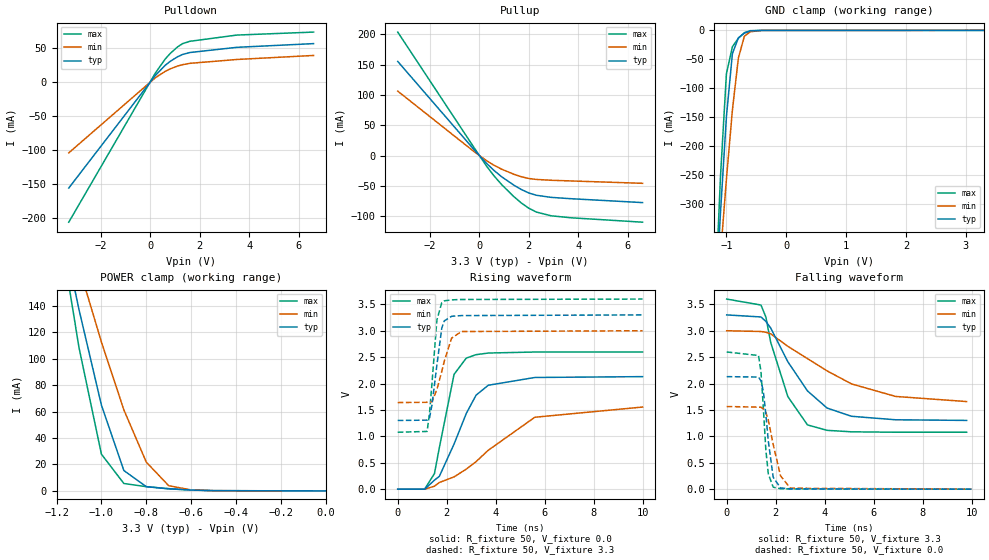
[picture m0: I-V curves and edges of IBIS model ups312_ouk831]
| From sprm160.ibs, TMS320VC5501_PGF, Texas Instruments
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[Model]   ups312_ouk831
Model_type   I/O
Vinh = 2.00
Vinl = 0.80
Enable   Active-Low
Polarity   Non-Inverting
| signals   A, GZ, Y
Vmeas = 1.5
|   typ   min   max
C_comp   2.553p   2.541p   2.555p
|   typ   min   max
[Temperature Range]   25   -40   125
|   typ   min   max
[Voltage Range]   3.30V   3.00V   3.60V
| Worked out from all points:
|   slope of the pulldown table from 0 to 0.495 V, typ, clamps not added: 24 ohm
|   slope of the pullup table from 0 to 0.495 V, typ, clamps not added: 23.8 ohm
|   GND clamp passes 1 mA (typ) near -0.60 V on its own axis
|   POWER clamp passes 1 mA (typ) near -0.64 V on its own axis
|   rising waveform, R_fixture 50, V_fixture 0.0: 20-80 % time 1.23ns typ, 2.49ns min, 656ps max; typ from 0 V to 2.13 V
|   falling waveform, R_fixture 50, V_fixture 3.3: 20-80 % time 1.7ns typ, 3.01ns min, 1ns max; typ from 3.3 V to 1.3 V
|   rising waveform, R_fixture 50, V_fixture 3.3: 20-80 % time 320ps typ, 467ps min, 255ps max; typ from 1.3 V to 3.3 V
|   falling waveform, R_fixture 50, V_fixture 0.0: 20-80 % time 289ps typ, 431ps min, 228ps max; typ from 2.13 V to 0 V
[Pulldown]
|   Voltage   I(typ)   I(min)   I(max)
-3.3V     -155.6mA   -104.1mA   -205.6mA
200mV     9.243mA    5.866mA    12.7mA
600mV     24.13mA    15.28mA    33.3mA
800mV     29.87mA    18.87mA    41.37mA
1.1V      36.63mA    23.02mA    51.08mA
1.3V      39.97mA    25.04mA    55.82mA
1.6V      42.83mA    27mA       59.29mA
3.5V      50.44mA    32.65mA    68.4mA
6.6V      55.87mA    38.54mA    72.75mA
[GND_clamp]
|   Voltage   I(typ)   I(min)   I(max)
-3.3V     -4.923A    -3.708A    -6.396A
-1.2V     -505mA     -529.2mA   -496.8mA
-1.1V     -317.1mA   -390.1mA   -254.5mA
-1V       -149.5mA   -257.6mA   -75.13mA
-900mV    -40.22mA   -138mA     -28.39mA
-800mV    -13.05mA   -47.86mA   -13.64mA
-700mV    -4.763mA   -10.19mA   -4.082mA
-600mV    -990.2uA   -2.384mA   -580.2uA
-400mV    -63.28uA   -85.04uA   -88.36uA
3.3V      355.3pA    30.66uA    -59.86uA
[Pullup]
|   Voltage   I(typ)   I(min)   I(max)
-3.3V     155.5mA    106.5mA    203.9mA
-200mV    9.306mA    6.233mA    12.42mA
300mV     -13.07mA   -8.546mA   -17.75mA
600mV     -24.68mA   -16mA      -33.65mA
900mV     -34.78mA   -22.33mA   -47.64mA
1.4V      -48.81mA   -30.78mA   -67.77mA
1.7V      -55.9mA    -34.78mA   -78.19mA
2V        -61.53mA   -37.68mA   -86.71mA
2.3V      -65.31mA   -39.22mA   -93.01mA
2.9V      -68.83mA   -40.61mA   -99.22mA
3.7V      -71.03mA   -41.73mA   -102.5mA
6.6V      -77.46mA   -45.65mA   -109.8mA
[POWER_clamp]
|   Voltage   I(typ)   I(min)   I(max)
-3.3V     2.112A     1.594A     2.742A
-1.2V     218.2mA    229.3mA    213.3mA
-1.1V     137.3mA    169.6mA    108.6mA
-1V       64.95mA    112.7mA    27.82mA
-900mV    15.44mA    61.33mA    5.616mA
-800mV    3.218mA    21.79mA    3.224mA
-700mV    1.543mA    3.926mA    1.724mA
-600mV    687.2uA    776.7uA    678uA
-500mV    216.3uA    199.4uA    185.5uA
0V        1pA        1pA        1pA
[Ramp]
|   I(typ)   I(min)   I(max)
dV/dt_r   1.278/1.222n   0.933/2.492n   1.559/0.651n
dV/dt_f   1.199/1.697n   0.806/3.013n   1.513/1.002n
[Rising Waveform]
R_fixture = 50
V_fixture = 0.0
|  pu_on
|  TIME   V(typ)   V(min)   V(max)
0s        6nV        19nV       5nV
1.1ns     -38.99uV   -123.7uV   2.338mV
1.5ns     170.2mV    55.66mV    294.4mV
1.7ns     242.6mV    126mV      786.2mV
2.3ns     853.4mV    232.3mV    2.173V
2.8ns     1.434V     379mV      2.482V
3.2ns     1.78V      521.6mV    2.547V
3.7ns     1.968V     737.5mV    2.578V
5.6ns     2.115V     1.362V     2.597V
10ns      2.131V     1.555V     2.598V
[Falling Waveform]
R_fixture = 50
V_fixture = 3.3
V_fixture_min = 3.0
V_fixture_max = 3.6
|  pd_on
|  TIME   V(typ)   V(min)   V(max)
0s        3.3V       3V         3.6V
1.4ns     3.261V     2.986V     3.487V
1.6ns     3.178V     2.972V     3.26V
1.8ns     3.05V      2.941V     2.776V
2.5ns     2.411V     2.705V     1.751V
3.3ns     1.861V     2.472V     1.217V
4.1ns     1.536V     2.24V      1.114V
5.1ns     1.38V      1.993V     1.086V
6.9ns     1.314V     1.756V     1.078V
9.8ns     1.302V     1.659V     1.078V
[Rising Waveform]
R_fixture = 50
V_fixture = 3.3
V_fixture_min = 3.0
V_fixture_max = 3.6
|  pd_off
|  TIME   V(typ)   V(min)   V(max)
0s        1.301V     1.64V      1.078V
1.2ns     1.307V     1.645V     1.093V
1.3ns     1.351V     1.649V     1.446V
1.4ns     1.6V       1.655V     2.01V
1.6ns     2.352V     1.888V     3.205V
1.8ns     3.051V     2.233V     3.532V
1.9ns     3.186V     2.421V     3.566V
2.2ns     3.274V     2.86V      3.585V
2.6ns     3.287V     2.985V     3.592V
10ns      3.3V       3V         3.6V
[Falling Waveform]
R_fixture = 50
V_fixture = 0.0
|  pu_off
|  TIME   V(typ)   V(min)   V(max)
0s        2.131V     1.565V     2.598V
1.3ns     2.123V     1.554V     2.531V
1.4ns     2.052V     1.55V      2.229V
1.5ns     1.846V     1.525V     1.517V
1.6ns     1.417V     1.453V     740.9mV
1.7ns     912.3mV    1.311V     288.5mV
1.9ns     223.6mV    846.1mV    38.11mV
2.2ns     23mV       251.7mV    7.072mV
2.6ns     5.593mV    18.04mV    3.563mV
10ns      12.77uV    69uV       400nV
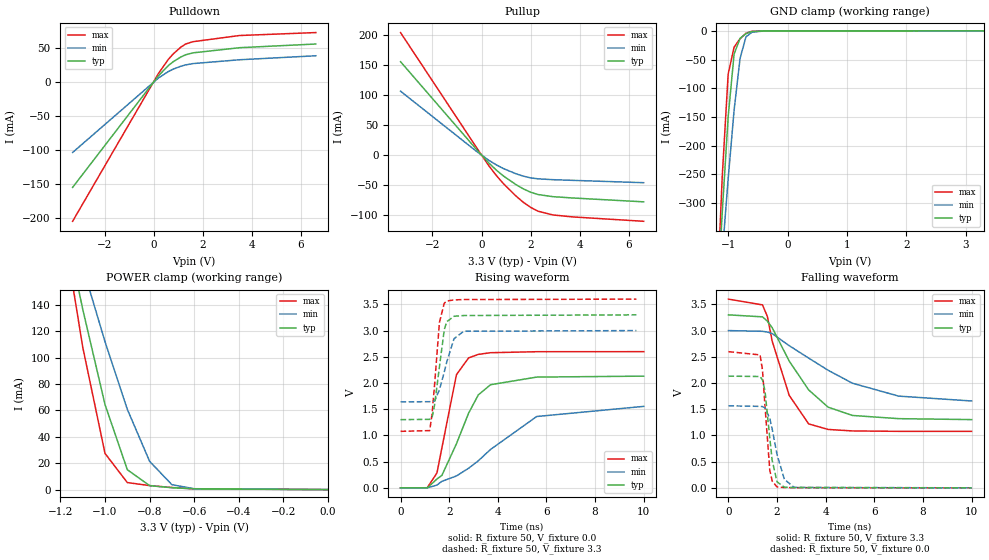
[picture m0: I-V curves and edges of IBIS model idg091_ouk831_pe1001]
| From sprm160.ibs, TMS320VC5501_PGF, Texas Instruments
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[Model]   idg091_ouk831_pe1001
| I/O with pulldown
Model_type   I/O
Vinh = 2.00
Vinl = 0.80
Enable   Active-Low
Polarity   Non-Inverting
| signals   A, GZ, Y
Vmeas = 1.5
|   typ   min   max
C_comp   1.997p   1.996p   1.999p
|   typ   min   max
[Temperature Range]   25   -40   125
|   typ   min   max
[Voltage Range]   3.30V   3.00V   3.60V
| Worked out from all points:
|   slope of the pulldown table from 0 to 0.495 V, typ, clamps not added: 24 ohm
|   slope of the pullup table from 0 to 0.495 V, typ, clamps not added: 23.8 ohm
|   GND clamp passes 1 mA (typ) near -0.60 V on its own axis
|   POWER clamp passes 1 mA (typ) near -0.65 V on its own axis
|   rising waveform, R_fixture 50, V_fixture 0.0: 20-80 % time 1.22ns typ, 2.48ns min, 657ps max; typ from 0 V to 2.13 V
|   falling waveform, R_fixture 50, V_fixture 3.3: 20-80 % time 1.7ns typ, 3.02ns min, 1.01ns max; typ from 3.3 V to 1.3 V
|   rising waveform, R_fixture 50, V_fixture 3.3: 20-80 % time 323ps typ, 470ps min, 259ps max; typ from 1.3 V to 3.3 V
|   falling waveform, R_fixture 50, V_fixture 0.0: 20-80 % time 296ps typ, 438ps min, 236ps max; typ from 2.13 V to 0 V
[Pulldown]
|   Voltage   I(typ)   I(min)   I(max)
-3.3V     -155.6mA   -104.1mA   -205.6mA
200mV     9.243mA    5.866mA    12.7mA
600mV     24.13mA    15.28mA    33.3mA
800mV     29.87mA    18.87mA    41.37mA
1.1V      36.63mA    23.02mA    51.08mA
1.3V      39.97mA    25.04mA    55.82mA
1.6V      42.83mA    27mA       59.29mA
3.5V      50.44mA    32.65mA    68.4mA
6.6V      55.87mA    38.54mA    72.75mA
[GND_clamp]
|   Voltage   I(typ)   I(min)   I(max)
-3.3V     -4.926A    -3.71A     -6.4A
-1.2V     -505.4mA   -529.6mA   -497.2mA
-1.1V     -317.4mA   -390.5mA   -254.7mA
-1V       -149.7mA   -257.9mA   -75.19mA
-900mV    -40.29mA   -138.2mA   -28.38mA
-800mV    -13.05mA   -47.97mA   -13.59mA
-700mV    -4.731mA   -10.23mA   -4.028mA
-600mV    -956.5uA   -2.389mA   -531.5uA
-400mV    -40.57uA   -71.55uA   -55.69uA
3.3V      100.3uA    53.84uA    176.6uA
[Pullup]
|   Voltage   I(typ)   I(min)   I(max)
-3.3V     155.5mA    106.5mA    203.9mA
-200mV    9.306mA    6.233mA    12.42mA
300mV     -13.07mA   -8.546mA   -17.75mA
600mV     -24.68mA   -16mA      -33.65mA
900mV     -34.78mA   -22.33mA   -47.64mA
1.4V      -48.81mA   -30.78mA   -67.77mA
1.7V      -55.9mA    -34.78mA   -78.19mA
2V        -61.53mA   -37.68mA   -86.71mA
2.3V      -65.31mA   -39.22mA   -93.01mA
2.9V      -68.83mA   -40.61mA   -99.22mA
3.7V      -71.03mA   -41.73mA   -102.5mA
6.6V      -77.46mA   -45.65mA   -109.8mA
[POWER_clamp]
|   Voltage   I(typ)   I(min)   I(max)
-3.3V     2.105A     1.588A     2.734A
-1.2V     217.1mA    228.2mA    212.4mA
-1.1V     136.6mA    168.7mA    107.9mA
-1V       64.4mA     112mA      27.37mA
-900mV    15.08mA    60.81mA    5.337mA
-800mV    3.01mA     21.44mA    3.051mA
-700mV    1.426mA    3.716mA    1.578mA
-600mV    596.1uA    671uA      553.1uA
0V        1pA        1pA        1pA
[Ramp]
|   I(typ)   I(min)   I(max)
dV/dt_r   1.278/1.219n   0.933/2.485n   1.559/0.652n
dV/dt_f   1.199/1.701n   0.806/3.022n   1.513/1.007n
[Rising Waveform]
R_fixture = 50
V_fixture = 0.0
|  pu_on
|  TIME   V(typ)   V(min)   V(max)
0s        3nV        15nV       2nV
1.1ns     39.4uV     -97.85uV   2.108mV
1.5ns     169mV      53.75mV    286.1mV
1.7ns     236.9mV    124.4mV    760.8mV
2.3ns     841mV      227.1mV    2.159V
2.8ns     1.425V     374.2mV    2.479V
3.2ns     1.774V     516.3mV    2.546V
3.7ns     1.967V     732.2mV    2.578V
5.6ns     2.113V     1.361V     2.597V
10ns      2.131V     1.554V     2.598V
[Falling Waveform]
R_fixture = 50
V_fixture = 3.3
V_fixture_min = 3.0
V_fixture_max = 3.6
|  pd_on
|  TIME   V(typ)   V(min)   V(max)
0s        3.3V       3V         3.6V
1.4ns     3.262V     2.986V     3.49V
1.6ns     3.18V      2.972V     3.27V
1.8ns     3.054V     2.942V     2.797V
2.5ns     2.418V     2.712V     1.764V
3.3ns     1.868V     2.475V     1.22V
4.1ns     1.539V     2.243V     1.114V
5.1ns     1.381V     1.996V     1.086V
7ns       1.32V      1.75V      1.078V
10ns      1.302V     1.657V     1.078V
[Rising Waveform]
R_fixture = 50
V_fixture = 3.3
V_fixture_min = 3.0
V_fixture_max = 3.6
|  pd_off
|  TIME   V(typ)   V(min)   V(max)
0s        1.301V     1.64V      1.078V
1.2ns     1.307V     1.644V     1.092V
1.3ns     1.346V     1.648V     1.421V
1.4ns     1.578V     1.654V     1.963V
1.6ns     2.309V     1.872V     3.155V
1.8ns     3.019V     2.211V     3.523V
1.9ns     3.169V     2.399V     3.564V
2.2ns     3.273V     2.845V     3.585V
2.6ns     3.287V     2.987V     3.592V
9.7ns     3.3V       3V         3.6V
[Falling Waveform]
R_fixture = 50
V_fixture = 0.0
|  pu_off
|  TIME   V(typ)   V(min)   V(max)
0s        2.131V     1.565V     2.598V
1.3ns     2.124V     1.554V     2.536V
1.4ns     2.057V     1.55V      2.251V
1.5ns     1.863V     1.527V     1.578V
1.7ns     949.1mV    1.325V     335.7mV
1.8ns     521.8mV    1.12V      129.2mV
2ns       113.9mV    632.2mV    16.55mV
2.3ns     13.39mV    163.8mV    5.982mV
2.7ns     5.138mV    9.688mV    3.068mV
10ns      8.669uV    61.41uV    411nV
